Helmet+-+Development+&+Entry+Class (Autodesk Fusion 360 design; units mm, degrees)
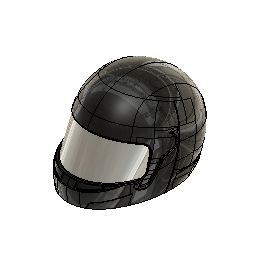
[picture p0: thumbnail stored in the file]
description: STEP AP214
part number: Final Helmet Shape For Dev and Entry
base_feature "Base Feature"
